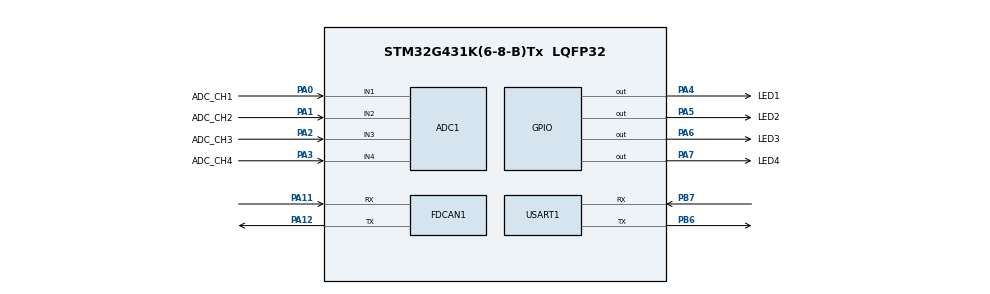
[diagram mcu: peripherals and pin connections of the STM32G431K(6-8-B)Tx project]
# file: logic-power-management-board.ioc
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ADC1.Channel-0\#ChannelRegularConversion=ADC_CHANNEL_1
ADC1.Channel-1\#ChannelRegularConversion=ADC_CHANNEL_2
ADC1.Channel-2\#ChannelRegularConversion=ADC_CHANNEL_3
ADC1.Channel-3\#ChannelRegularConversion=ADC_CHANNEL_4
ADC1.ContinuousConvMode=ENABLE
ADC1.DMAContinuousRequests=ENABLE
ADC1.NbrOfConversion=4
ADC1.NbrOfConversionFlag=1
ADC1.OffsetNumber-0\#ChannelRegularConversion=ADC_OFFSET_NONE
ADC1.OffsetNumber-1\#ChannelRegularConversion=ADC_OFFSET_NONE
ADC1.OffsetNumber-2\#ChannelRegularConversion=ADC_OFFSET_NONE
ADC1.OffsetNumber-3\#ChannelRegularConversion=ADC_OFFSET_NONE
ADC1.Overrun=ADC_OVR_DATA_OVERWRITTEN
ADC1.Rank-0\#ChannelRegularConversion=1
ADC1.Rank-1\#ChannelRegularConversion=2
ADC1.Rank-2\#ChannelRegularConversion=3
ADC1.Rank-3\#ChannelRegularConversion=4
ADC1.SamplingTime-0\#ChannelRegularConversion=ADC_SAMPLETIME_640CYCLES_5
ADC1.SamplingTime-1\#ChannelRegularConversion=ADC_SAMPLETIME_2CYCLES_5
ADC1.SamplingTime-2\#ChannelRegularConversion=ADC_SAMPLETIME_640CYCLES_5
ADC1.SamplingTime-3\#ChannelRegularConversion=ADC_SAMPLETIME_640CYCLES_5
ADC1.master=1
Dma.ADC1.0.Direction=DMA_PERIPH_TO_MEMORY
Dma.ADC1.0.EventEnable=DISABLE
Dma.ADC1.0.Instance=DMA1_Channel1
Dma.ADC1.0.MemDataAlignment=DMA_MDATAALIGN_HALFWORD
Dma.ADC1.0.MemInc=DMA_MINC_ENABLE
Dma.ADC1.0.Mode=DMA_CIRCULAR
Dma.ADC1.0.PeriphDataAlignment=DMA_PDATAALIGN_HALFWORD
Dma.ADC1.0.PeriphInc=DMA_PINC_DISABLE
Dma.ADC1.0.Polarity=HAL_DMAMUX_REQ_GEN_RISING
Dma.ADC1.0.Priority=DMA_PRIORITY_LOW
Dma.ADC1.0.RequestNumber=1
Dma.ADC1.0.SignalID=NONE
Dma.ADC1.0.SyncEnable=DISABLE
Dma.ADC1.0.SyncPolarity=HAL_DMAMUX_SYNC_NO_EVENT
Dma.ADC1.0.SyncRequestNumber=1
Dma.ADC1.0.SyncSignalID=NONE
Dma.Request0=ADC1
FDCAN1.CalculateBaudRateNominal=1000000
FDCAN1.CalculateTimeBitNominal=1000
FDCAN1.CalculateTimeQuantumNominal=62.5
FDCAN1.ClockDivider=FDCAN_CLOCK_DIV1
FDCAN1.ExtFiltersNbr=1
FDCAN1.FrameFormat=FDCAN_FRAME_FD_NO_BRS
FDCAN1.NominalPrescaler=8
FDCAN1.NominalSyncJumpWidth=2
FDCAN1.NominalTimeSeg1=12
FDCAN1.NominalTimeSeg2=3
FDCAN1.StdFiltersNbr=1
Mcu.Family=STM32G4
Mcu.Name=STM32G431K(6-8-B)Tx
Mcu.Package=LQFP32
NVIC.DMA1_Channel1_IRQn=true\:3\:0\:true\:false\:true\:false\:true\:true
NVIC.FDCAN1_IT0_IRQn=true\:1\:0\:true\:false\:true\:true\:true\:true
NVIC.PriorityGroup=NVIC_PRIORITYGROUP_4
PA0.GPIO_Label=ADC_CH1
PA0.Mode=IN1-Single-Ended
PA0.Signal=ADC1_IN1
PA1.GPIO_Label=ADC_CH2
PA1.Mode=IN2-Single-Ended
PA1.Signal=ADC1_IN2
PA11.Mode=FDCAN_Activate
PA11.Signal=FDCAN1_RX
PA12.Mode=FDCAN_Activate
PA12.Signal=FDCAN1_TX
PA13.Mode=Serial_Wire
PA13.Signal=SYS_JTMS-SWDIO
PA14.Mode=Serial_Wire
PA14.Signal=SYS_JTCK-SWCLK
PA2.GPIO_Label=ADC_CH3
PA2.Mode=IN3-Single-Ended
PA2.Signal=ADC1_IN3
PA3.GPIO_Label=ADC_CH4
PA3.Mode=IN4-Single-Ended
PA3.Signal=ADC1_IN4
PA4.GPIO_Label=LED1
PA4.Signal=GPIO_Output
PA5.GPIO_Label=LED2
PA5.Signal=GPIO_Output
PA6.GPIO_Label=LED3
PA6.Signal=GPIO_Output
PA7.GPIO_Label=LED4
PA7.Signal=GPIO_Output
PB6.Mode=Asynchronous
PB6.Signal=USART1_TX
PB7.Mode=Asynchronous
PB7.Signal=USART1_RX
ProjectManager.HeapSize=0x200
ProjectManager.StackSize=0x400
ProjectManager.TargetToolchain=CMake
RCC.ADC12Freq_Value=128000000
RCC.AHBFreq_Value=128000000
RCC.APB1Freq_Value=128000000
RCC.APB1TimFreq_Value=128000000
RCC.APB2Freq_Value=128000000
RCC.APB2TimFreq_Value=128000000
RCC.CortexFreq_Value=128000000
RCC.EXTERNAL_CLOCK_VALUE=12288000
RCC.HCLKFreq_Value=128000000
RCC.HSE_VALUE=8000000
RCC.HSI48_VALUE=48000000
RCC.HSI_VALUE=16000000
RCC.LSE_VALUE=32768
RCC.PLLN=16
RCC.SYSCLKFreq_VALUE=128000000
RCC.SYSCLKSource=RCC_SYSCLKSOURCE_PLLCLK
RCC.USBFreq_Value=128000000
RCC.VCOOutputFreq_Value=256000000
USART1.VirtualMode-Asynchronous=VM_ASYNC
VP_SYS_VS_DBSignals.Mode=DisableDeadBatterySignals
board=custom

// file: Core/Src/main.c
/* USER CODE BEGIN Header */
/**
 ******************************************************************************
 * @file           : main.c
 * @brief          : Main program body
 ******************************************************************************
 * @attention
 *
 * Copyright (c) 2026 STMicroelectronics.
 * All rights reserved.
 *
 * This software is licensed under terms that can be found in the LICENSE file
 * in the root directory of this software component.
 * If no LICENSE file comes with this software, it is provided AS-IS.
 *
 ******************************************************************************
 */
/* USER CODE END Header */
#include "main.h"

#include "adc.h"
#include "dma.h"
#include "fdcan.h"
#include "gpio.h"
#include "usart.h"

/* USER CODE BEGIN Includes */
#include "app/app.hpp"
/* USER CODE END Includes */

void SystemClock_Config(void);

int main(void)
{

    /* MCU Configuration--------------------------------------------------------*/

    /* Reset of all peripherals, Initializes the Flash interface and the Systick. */
    HAL_Init();

    /* Configure the system clock */
    SystemClock_Config();

    /* Initialize all configured peripherals */
    MX_GPIO_Init();
    MX_DMA_Init();
    MX_ADC1_Init();
    MX_FDCAN1_Init();
    MX_USART1_UART_Init();
    /* USER CODE BEGIN 2 */
    setup();
    /* USER CODE END 2 */

    /* Infinite loop */
    while (1) {

        /* USER CODE BEGIN 3 */
        loop();
    }
    /* USER CODE END 3 */
}

void SystemClock_Config(void)
{
    RCC_OscInitTypeDef RCC_OscInitStruct = {0};
    RCC_ClkInitTypeDef RCC_ClkInitStruct = {0};

    /** Configure the main internal regulator output voltage
     */
    HAL_PWREx_ControlVoltageScaling(PWR_REGULATOR_VOLTAGE_SCALE1_BOOST);

    /** Initializes the RCC Oscillators according to the specified parameters
     * in the RCC_OscInitTypeDef structure.
     */
    RCC_OscInitStruct.OscillatorType      = RCC_OSCILLATORTYPE_HSI;
    RCC_OscInitStruct.HSIState            = RCC_HSI_ON;
    RCC_OscInitStruct.HSICalibrationValue = RCC_HSICALIBRATION_DEFAULT;
    RCC_OscInitStruct.PLL.PLLState        = RCC_PLL_ON;
    RCC_OscInitStruct.PLL.PLLSource       = RCC_PLLSOURCE_HSI;
    RCC_OscInitStruct.PLL.PLLM            = RCC_PLLM_DIV1;
    RCC_OscInitStruct.PLL.PLLN            = 20;
    RCC_OscInitStruct.PLL.PLLP            = RCC_PLLP_DIV2;
    RCC_OscInitStruct.PLL.PLLQ            = RCC_PLLQ_DIV2;
    RCC_OscInitStruct.PLL.PLLR            = RCC_PLLR_DIV2;
    if (HAL_RCC_OscConfig(&RCC_OscInitStruct) != HAL_OK) {
        Error_Handler();
    }

    /** Initializes the CPU, AHB and APB buses clocks
     */
    RCC_ClkInitStruct.ClockType =
        RCC_CLOCKTYPE_HCLK | RCC_CLOCKTYPE_SYSCLK | RCC_CLOCKTYPE_PCLK1 | RCC_CLOCKTYPE_PCLK2;
    RCC_ClkInitStruct.SYSCLKSource   = RCC_SYSCLKSOURCE_PLLCLK;
    RCC_ClkInitStruct.AHBCLKDivider  = RCC_SYSCLK_DIV1;
    RCC_ClkInitStruct.APB1CLKDivider = RCC_HCLK_DIV1;
    RCC_ClkInitStruct.APB2CLKDivider = RCC_HCLK_DIV1;

    if (HAL_RCC_ClockConfig(&RCC_ClkInitStruct, FLASH_LATENCY_4) != HAL_OK) {
        Error_Handler();
    }
}

void Error_Handler(void)
{
    __disable_irq();
    while (1) {
    }
}
